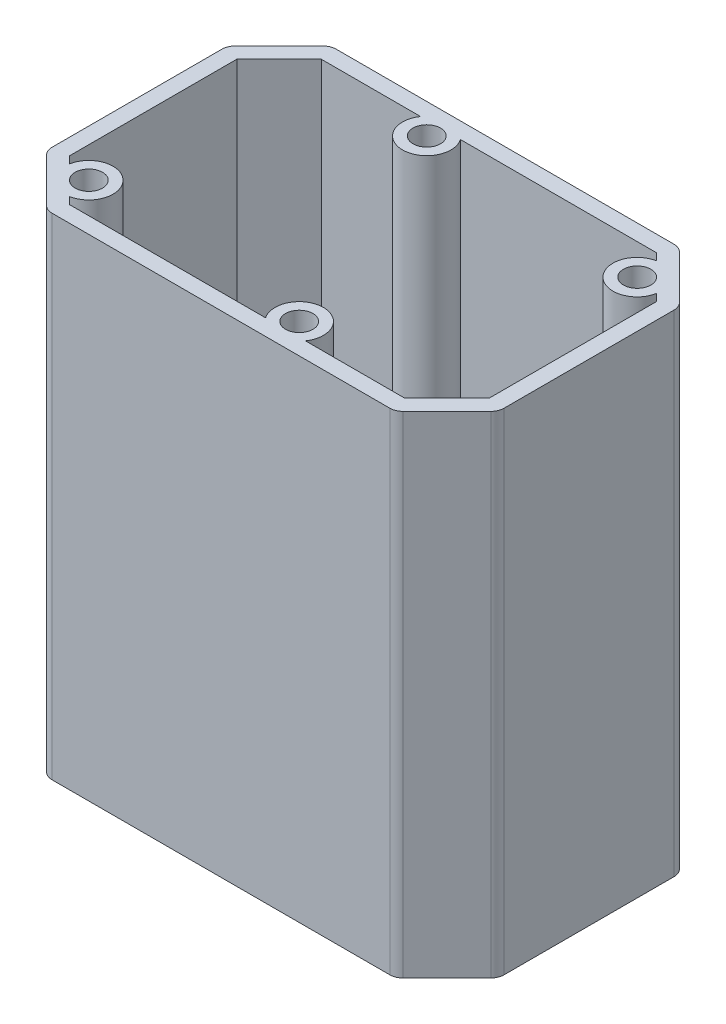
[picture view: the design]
ISO-10303-21;
HEADER;
FILE_DESCRIPTION(('STEP AP214'),'2;1');
FILE_NAME('part.step','',(''),(''),'','','');
FILE_SCHEMA(('AUTOMOTIVE_DESIGN { 1 0 10303 214 1 1 1 1 }'));
ENDSEC;
DATA;
#1=APPLICATION_CONTEXT('core data for automotive mechanical design processes');
#2=APPLICATION_PROTOCOL_DEFINITION('international standard','automotive_design',2000,#1);
#3=PRODUCT_CONTEXT('',#1,'mechanical');
#4=PRODUCT('Part','Part','',(#3));
#5=PRODUCT_RELATED_PRODUCT_CATEGORY('part','',(#4));
#6=PRODUCT_DEFINITION_FORMATION('','',#4);
#7=PRODUCT_DEFINITION_CONTEXT('part definition',#1,'design');
#8=PRODUCT_DEFINITION('design','',#6,#7);
#9=PRODUCT_DEFINITION_SHAPE('','',#8);
#10=(LENGTH_UNIT() NAMED_UNIT(*) SI_UNIT(.MILLI.,.METRE.));
#11=(NAMED_UNIT(*) PLANE_ANGLE_UNIT() SI_UNIT($,.RADIAN.));
#12=(NAMED_UNIT(*) SI_UNIT($,.STERADIAN.) SOLID_ANGLE_UNIT());
#13=UNCERTAINTY_MEASURE_WITH_UNIT(LENGTH_MEASURE(1.E-05),#10,'distance_accuracy_value','');
#14=(GEOMETRIC_REPRESENTATION_CONTEXT(3) GLOBAL_UNCERTAINTY_ASSIGNED_CONTEXT((#13)) GLOBAL_UNIT_ASSIGNED_CONTEXT((#10,
#11,#12)) REPRESENTATION_CONTEXT('',''));
#15=CARTESIAN_POINT('',(0.,0.,0.));
#16=DIRECTION('',(0.,0.,1.));
#17=DIRECTION('',(1.,0.,0.));
#18=AXIS2_PLACEMENT_3D('',#15,#16,#17);
#19=CARTESIAN_POINT('',(24.5000000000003,76.,-24.5000000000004));
#20=DIRECTION('',(-0.707106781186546,0.,0.707106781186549));
#21=DIRECTION('',(0.707106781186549,0.,0.707106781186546));
#22=AXIS2_PLACEMENT_3D('',#19,#20,#21);
#23=PLANE('',#22);
#24=DIRECTION('',(-0.707106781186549,0.,-0.707106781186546));
#25=VECTOR('',#24,1.);
#26=CARTESIAN_POINT('',(24.5000000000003,0.,-24.5000000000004));
#27=LINE('',#26,#25);
#28=CARTESIAN_POINT('',(34.4142135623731,0.,-14.5857864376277));
#29=VERTEX_POINT('',#28);
#30=CARTESIAN_POINT('',(27.5857864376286,0.,-21.4142135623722));
#31=VERTEX_POINT('',#30);
#32=EDGE_CURVE('E337',#29,#31,#27,.T.);
#33=ORIENTED_EDGE('',*,*,#32,.T.);
#34=DIRECTION('',(0.,-1.,0.));
#35=VECTOR('',#34,1.);
#36=CARTESIAN_POINT('',(27.5857864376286,76.,-21.4142135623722));
#37=LINE('',#36,#35);
#38=CARTESIAN_POINT('',(27.5857864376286,76.,-21.4142135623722));
#39=VERTEX_POINT('',#38);
#40=EDGE_CURVE('E11',#39,#31,#37,.T.);
#41=ORIENTED_EDGE('',*,*,#40,.F.);
#42=DIRECTION('',(-0.707106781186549,0.,-0.707106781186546));
#43=VECTOR('',#42,1.);
#44=CARTESIAN_POINT('',(24.5000000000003,76.,-24.5000000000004));
#45=LINE('',#44,#43);
#46=CARTESIAN_POINT('',(34.4142135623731,76.,-14.5857864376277));
#47=VERTEX_POINT('',#46);
#48=EDGE_CURVE('E914',#47,#39,#45,.T.);
#49=ORIENTED_EDGE('',*,*,#48,.F.);
#50=DIRECTION('',(0.,-1.,0.));
#51=VECTOR('',#50,1.);
#52=CARTESIAN_POINT('',(34.4142135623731,76.,-14.5857864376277));
#53=LINE('',#52,#51);
#54=EDGE_CURVE('E368',#47,#29,#53,.T.);
#55=ORIENTED_EDGE('',*,*,#54,.T.);
#56=EDGE_LOOP('',(#33,#41,#49,#55));
#57=FACE_BOUND('',#56,.T.);
#58=ADVANCED_FACE('F41',(#57),#23,.F.);
#59=CARTESIAN_POINT('',(26.1715728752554,76.,-19.9999999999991));
#60=DIRECTION('',(0.,-1.,0.));
#61=DIRECTION('',(0.,0.,-1.));
#62=AXIS2_PLACEMENT_3D('',#59,#60,#61);
#63=CYLINDRICAL_SURFACE('',#62,2.00000000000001);
#64=CARTESIAN_POINT('',(26.1715728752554,0.,-19.9999999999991));
#65=DIRECTION('',(0.,1.,0.));
#66=DIRECTION('',(0.,0.,1.));
#67=AXIS2_PLACEMENT_3D('',#64,#65,#66);
#68=CIRCLE('',#67,2.00000000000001);
#69=CARTESIAN_POINT('',(26.1715728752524,0.,-21.9999999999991));
#70=VERTEX_POINT('',#69);
#71=EDGE_CURVE('E340',#31,#70,#68,.T.);
#72=ORIENTED_EDGE('',*,*,#71,.T.);
#73=DIRECTION('',(0.,-1.,0.));
#74=VECTOR('',#73,1.);
#75=CARTESIAN_POINT('',(26.1715728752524,76.,-21.9999999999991));
#76=LINE('',#75,#74);
#77=CARTESIAN_POINT('',(26.1715728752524,76.,-21.9999999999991));
#78=VERTEX_POINT('',#77);
#79=EDGE_CURVE('E51',#78,#70,#76,.T.);
#80=ORIENTED_EDGE('',*,*,#79,.F.);
#81=CARTESIAN_POINT('',(26.1715728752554,76.,-19.9999999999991));
#82=DIRECTION('',(0.,1.,0.));
#83=DIRECTION('',(0.,0.,1.));
#84=AXIS2_PLACEMENT_3D('',#81,#82,#83);
#85=CIRCLE('',#84,2.00000000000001);
#86=EDGE_CURVE('E915',#39,#78,#85,.T.);
#87=ORIENTED_EDGE('',*,*,#86,.F.);
#88=ORIENTED_EDGE('',*,*,#40,.T.);
#89=EDGE_LOOP('',(#72,#80,#87,#88));
#90=FACE_BOUND('',#89,.T.);
#91=ADVANCED_FACE('F531',(#90),#63,.T.);
#92=CARTESIAN_POINT('',(3.42681749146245E-13,76.,-21.9999999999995));
#93=DIRECTION('',(0.,0.,1.));
#94=DIRECTION('',(1.,0.,0.));
#95=AXIS2_PLACEMENT_3D('',#92,#93,#94);
#96=PLANE('',#95);
#97=DIRECTION('',(-1.,0.,0.));
#98=VECTOR('',#97,1.);
#99=CARTESIAN_POINT('',(3.42681749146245E-13,0.,-21.9999999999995));
#100=LINE('',#99,#98);
#101=CARTESIAN_POINT('',(-26.1715728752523,0.,-21.9999999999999));
#102=VERTEX_POINT('',#101);
#103=EDGE_CURVE('E342',#70,#102,#100,.T.);
#104=ORIENTED_EDGE('',*,*,#103,.T.);
#105=DIRECTION('',(0.,-1.,0.));
#106=VECTOR('',#105,1.);
#107=CARTESIAN_POINT('',(-26.1715728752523,76.,-21.9999999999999));
#108=LINE('',#107,#106);
#109=CARTESIAN_POINT('',(-26.1715728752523,76.,-21.9999999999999));
#110=VERTEX_POINT('',#109);
#111=EDGE_CURVE('E399',#110,#102,#108,.T.);
#112=ORIENTED_EDGE('',*,*,#111,.F.);
#113=DIRECTION('',(-1.,0.,0.));
#114=VECTOR('',#113,1.);
#115=CARTESIAN_POINT('',(3.42681749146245E-13,76.,-21.9999999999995));
#116=LINE('',#115,#114);
#117=EDGE_CURVE('E917',#78,#110,#116,.T.);
#118=ORIENTED_EDGE('',*,*,#117,.F.);
#119=ORIENTED_EDGE('',*,*,#79,.T.);
#120=EDGE_LOOP('',(#104,#112,#118,#119));
#121=FACE_BOUND('',#120,.T.);
#122=ADVANCED_FACE('F537',(#121),#96,.F.);
#123=CARTESIAN_POINT('',(-26.1715728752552,76.,-19.9999999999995));
#124=DIRECTION('',(0.,-1.,0.));
#125=DIRECTION('',(0.,0.,-1.));
#126=AXIS2_PLACEMENT_3D('',#123,#124,#125);
#127=CYLINDRICAL_SURFACE('',#126,2.00000000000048);
#128=CARTESIAN_POINT('',(-26.1715728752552,0.,-19.9999999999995));
#129=DIRECTION('',(0.,1.,0.));
#130=DIRECTION('',(0.,0.,1.));
#131=AXIS2_PLACEMENT_3D('',#128,#129,#130);
#132=CIRCLE('',#131,2.00000000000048);
#133=CARTESIAN_POINT('',(-27.5857864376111,0.,-21.4142135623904));
#134=VERTEX_POINT('',#133);
#135=EDGE_CURVE('E344',#102,#134,#132,.T.);
#136=ORIENTED_EDGE('',*,*,#135,.T.);
#137=DIRECTION('',(0.,-1.,0.));
#138=VECTOR('',#137,1.);
#139=CARTESIAN_POINT('',(-27.5857864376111,76.,-21.4142135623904));
#140=LINE('',#139,#138);
#141=CARTESIAN_POINT('',(-27.5857864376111,76.,-21.4142135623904));
#142=VERTEX_POINT('',#141);
#143=EDGE_CURVE('E396',#142,#134,#140,.T.);
#144=ORIENTED_EDGE('',*,*,#143,.F.);
#145=CARTESIAN_POINT('',(-26.1715728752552,76.,-19.9999999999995));
#146=DIRECTION('',(0.,1.,0.));
#147=DIRECTION('',(0.,0.,1.));
#148=AXIS2_PLACEMENT_3D('',#145,#146,#147);
#149=CIRCLE('',#148,2.00000000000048);
#150=EDGE_CURVE('E879',#110,#142,#149,.T.);
#151=ORIENTED_EDGE('',*,*,#150,.F.);
#152=ORIENTED_EDGE('',*,*,#111,.T.);
#153=EDGE_LOOP('',(#136,#144,#151,#152));
#154=FACE_BOUND('',#153,.T.);
#155=ADVANCED_FACE('F828',(#154),#127,.T.);
#156=CARTESIAN_POINT('',(-24.5000000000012,76.,-24.5000000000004));
#157=DIRECTION('',(0.707106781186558,0.,0.707106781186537));
#158=DIRECTION('',(0.707106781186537,0.,-0.707106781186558));
#159=AXIS2_PLACEMENT_3D('',#156,#157,#158);
#160=PLANE('',#159);
#161=DIRECTION('',(-0.707106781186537,0.,0.707106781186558));
#162=VECTOR('',#161,1.);
#163=CARTESIAN_POINT('',(-24.5000000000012,0.,-24.5000000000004));
#164=LINE('',#163,#162);
#165=CARTESIAN_POINT('',(-34.4142135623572,0.,-14.5857864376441));
#166=VERTEX_POINT('',#165);
#167=EDGE_CURVE('E346',#134,#166,#164,.T.);
#168=ORIENTED_EDGE('',*,*,#167,.T.);
#169=DIRECTION('',(0.,-1.,0.));
#170=VECTOR('',#169,1.);
#171=CARTESIAN_POINT('',(-34.4142135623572,76.,-14.5857864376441));
#172=LINE('',#171,#170);
#173=CARTESIAN_POINT('',(-34.4142135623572,76.,-14.5857864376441));
#174=VERTEX_POINT('',#173);
#175=EDGE_CURVE('E393',#174,#166,#172,.T.);
#176=ORIENTED_EDGE('',*,*,#175,.F.);
#177=DIRECTION('',(-0.707106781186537,0.,0.707106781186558));
#178=VECTOR('',#177,1.);
#179=CARTESIAN_POINT('',(-24.5000000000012,76.,-24.5000000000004));
#180=LINE('',#179,#178);
#181=EDGE_CURVE('E891',#142,#174,#180,.T.);
#182=ORIENTED_EDGE('',*,*,#181,.F.);
#183=ORIENTED_EDGE('',*,*,#143,.T.);
#184=EDGE_LOOP('',(#168,#176,#182,#183));
#185=FACE_BOUND('',#184,.T.);
#186=ADVANCED_FACE('F819',(#185),#160,.F.);
#187=CARTESIAN_POINT('',(-32.9999999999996,76.,-13.1715728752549));
#188=DIRECTION('',(0.,-1.,0.));
#189=DIRECTION('',(0.,0.,-1.));
#190=AXIS2_PLACEMENT_3D('',#187,#188,#189);
#191=CYLINDRICAL_SURFACE('',#190,2.00000000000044);
#192=CARTESIAN_POINT('',(-32.9999999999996,0.,-13.1715728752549));
#193=DIRECTION('',(0.,1.,0.));
#194=DIRECTION('',(0.,0.,1.));
#195=AXIS2_PLACEMENT_3D('',#192,#193,#194);
#196=CIRCLE('',#195,2.00000000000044);
#197=CARTESIAN_POINT('',(-35.,0.,-13.1715728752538));
#198=VERTEX_POINT('',#197);
#199=EDGE_CURVE('E348',#166,#198,#196,.T.);
#200=ORIENTED_EDGE('',*,*,#199,.T.);
#201=DIRECTION('',(0.,-1.,0.));
#202=VECTOR('',#201,1.);
#203=CARTESIAN_POINT('',(-35.,76.,-13.1715728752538));
#204=LINE('',#203,#202);
#205=CARTESIAN_POINT('',(-35.,76.,-13.1715728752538));
#206=VERTEX_POINT('',#205);
#207=EDGE_CURVE('E390',#206,#198,#204,.T.);
#208=ORIENTED_EDGE('',*,*,#207,.F.);
#209=CARTESIAN_POINT('',(-32.9999999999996,76.,-13.1715728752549));
#210=DIRECTION('',(0.,1.,0.));
#211=DIRECTION('',(0.,0.,1.));
#212=AXIS2_PLACEMENT_3D('',#209,#210,#211);
#213=CIRCLE('',#212,2.00000000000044);
#214=EDGE_CURVE('E888',#174,#206,#213,.T.);
#215=ORIENTED_EDGE('',*,*,#214,.F.);
#216=ORIENTED_EDGE('',*,*,#175,.T.);
#217=EDGE_LOOP('',(#200,#208,#215,#216));
#218=FACE_BOUND('',#217,.T.);
#219=ADVANCED_FACE('F810',(#218),#191,.T.);
#220=CARTESIAN_POINT('',(-35.,76.,0.));
#221=DIRECTION('',(1.,0.,0.));
#222=DIRECTION('',(0.,0.,-1.));
#223=AXIS2_PLACEMENT_3D('',#220,#221,#222);
#224=PLANE('',#223);
#225=DIRECTION('',(0.,0.,1.));
#226=VECTOR('',#225,1.);
#227=CARTESIAN_POINT('',(-35.,0.,0.));
#228=LINE('',#227,#226);
#229=CARTESIAN_POINT('',(-35.,0.,13.1715728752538));
#230=VERTEX_POINT('',#229);
#231=EDGE_CURVE('E350',#198,#230,#228,.T.);
#232=ORIENTED_EDGE('',*,*,#231,.T.);
#233=DIRECTION('',(0.,-1.,0.));
#234=VECTOR('',#233,1.);
#235=CARTESIAN_POINT('',(-35.,76.,13.1715728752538));
#236=LINE('',#235,#234);
#237=CARTESIAN_POINT('',(-35.,76.,13.1715728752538));
#238=VERTEX_POINT('',#237);
#239=EDGE_CURVE('E387',#238,#230,#236,.T.);
#240=ORIENTED_EDGE('',*,*,#239,.F.);
#241=DIRECTION('',(0.,0.,1.));
#242=VECTOR('',#241,1.);
#243=CARTESIAN_POINT('',(-35.,76.,0.));
#244=LINE('',#243,#242);
#245=EDGE_CURVE('E890',#206,#238,#244,.T.);
#246=ORIENTED_EDGE('',*,*,#245,.F.);
#247=ORIENTED_EDGE('',*,*,#207,.T.);
#248=EDGE_LOOP('',(#232,#240,#246,#247));
#249=FACE_BOUND('',#248,.T.);
#250=ADVANCED_FACE('F801',(#249),#224,.F.);
#251=CARTESIAN_POINT('',(-33.,76.,13.1715728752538));
#252=DIRECTION('',(0.,-1.,0.));
#253=DIRECTION('',(0.,0.,-1.));
#254=AXIS2_PLACEMENT_3D('',#251,#252,#253);
#255=CYLINDRICAL_SURFACE('',#254,2.);
#256=CARTESIAN_POINT('',(-33.,0.,13.1715728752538));
#257=DIRECTION('',(0.,1.,0.));
#258=DIRECTION('',(0.,0.,1.));
#259=AXIS2_PLACEMENT_3D('',#256,#257,#258);
#260=CIRCLE('',#259,2.);
#261=CARTESIAN_POINT('',(-34.4142135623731,0.,14.5857864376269));
#262=VERTEX_POINT('',#261);
#263=EDGE_CURVE('E352',#230,#262,#260,.T.);
#264=ORIENTED_EDGE('',*,*,#263,.T.);
#265=DIRECTION('',(0.,-1.,0.));
#266=VECTOR('',#265,1.);
#267=CARTESIAN_POINT('',(-34.4142135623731,76.,14.5857864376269));
#268=LINE('',#267,#266);
#269=CARTESIAN_POINT('',(-34.4142135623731,76.,14.5857864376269));
#270=VERTEX_POINT('',#269);
#271=EDGE_CURVE('E384',#270,#262,#268,.T.);
#272=ORIENTED_EDGE('',*,*,#271,.F.);
#273=CARTESIAN_POINT('',(-33.,76.,13.1715728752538));
#274=DIRECTION('',(0.,1.,0.));
#275=DIRECTION('',(0.,0.,1.));
#276=AXIS2_PLACEMENT_3D('',#273,#274,#275);
#277=CIRCLE('',#276,2.);
#278=EDGE_CURVE('E893',#238,#270,#277,.T.);
#279=ORIENTED_EDGE('',*,*,#278,.F.);
#280=ORIENTED_EDGE('',*,*,#239,.T.);
#281=EDGE_LOOP('',(#264,#272,#279,#280));
#282=FACE_BOUND('',#281,.T.);
#283=ADVANCED_FACE('F792',(#282),#255,.T.);
#284=CARTESIAN_POINT('',(-24.4999999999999,76.,24.5));
#285=DIRECTION('',(0.707106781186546,0.,-0.707106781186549));
#286=DIRECTION('',(-0.707106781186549,0.,-0.707106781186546));
#287=AXIS2_PLACEMENT_3D('',#284,#285,#286);
#288=PLANE('',#287);
#289=DIRECTION('',(0.707106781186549,0.,0.707106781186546));
#290=VECTOR('',#289,1.);
#291=CARTESIAN_POINT('',(-24.4999999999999,0.,24.5));
#292=LINE('',#291,#290);
#293=CARTESIAN_POINT('',(-27.5857864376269,0.,21.4142135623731));
#294=VERTEX_POINT('',#293);
#295=EDGE_CURVE('E354',#262,#294,#292,.T.);
#296=ORIENTED_EDGE('',*,*,#295,.T.);
#297=DIRECTION('',(0.,-1.,0.));
#298=VECTOR('',#297,1.);
#299=CARTESIAN_POINT('',(-27.5857864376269,76.,21.4142135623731));
#300=LINE('',#299,#298);
#301=CARTESIAN_POINT('',(-27.5857864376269,76.,21.4142135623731));
#302=VERTEX_POINT('',#301);
#303=EDGE_CURVE('E381',#302,#294,#300,.T.);
#304=ORIENTED_EDGE('',*,*,#303,.F.);
#305=DIRECTION('',(0.707106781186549,0.,0.707106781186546));
#306=VECTOR('',#305,1.);
#307=CARTESIAN_POINT('',(-24.4999999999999,76.,24.5));
#308=LINE('',#307,#306);
#309=EDGE_CURVE('E899',#270,#302,#308,.T.);
#310=ORIENTED_EDGE('',*,*,#309,.F.);
#311=ORIENTED_EDGE('',*,*,#271,.T.);
#312=EDGE_LOOP('',(#296,#304,#310,#311));
#313=FACE_BOUND('',#312,.T.);
#314=ADVANCED_FACE('F783',(#313),#288,.F.);
#315=CARTESIAN_POINT('',(-26.1715728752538,76.,20.));
#316=DIRECTION('',(0.,-1.,0.));
#317=DIRECTION('',(0.,0.,-1.));
#318=AXIS2_PLACEMENT_3D('',#315,#316,#317);
#319=CYLINDRICAL_SURFACE('',#318,1.99999999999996);
#320=CARTESIAN_POINT('',(-26.1715728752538,0.,20.));
#321=DIRECTION('',(0.,1.,0.));
#322=DIRECTION('',(0.,0.,1.));
#323=AXIS2_PLACEMENT_3D('',#320,#321,#322);
#324=CIRCLE('',#323,1.99999999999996);
#325=CARTESIAN_POINT('',(-26.1715728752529,0.,22.));
#326=VERTEX_POINT('',#325);
#327=EDGE_CURVE('E356',#294,#326,#324,.T.);
#328=ORIENTED_EDGE('',*,*,#327,.T.);
#329=DIRECTION('',(0.,-1.,0.));
#330=VECTOR('',#329,1.);
#331=CARTESIAN_POINT('',(-26.1715728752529,76.,22.));
#332=LINE('',#331,#330);
#333=CARTESIAN_POINT('',(-26.1715728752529,76.,22.));
#334=VERTEX_POINT('',#333);
#335=EDGE_CURVE('E378',#334,#326,#332,.T.);
#336=ORIENTED_EDGE('',*,*,#335,.F.);
#337=CARTESIAN_POINT('',(-26.1715728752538,76.,20.));
#338=DIRECTION('',(0.,1.,0.));
#339=DIRECTION('',(0.,0.,1.));
#340=AXIS2_PLACEMENT_3D('',#337,#338,#339);
#341=CIRCLE('',#340,1.99999999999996);
#342=EDGE_CURVE('E901',#302,#334,#341,.T.);
#343=ORIENTED_EDGE('',*,*,#342,.F.);
#344=ORIENTED_EDGE('',*,*,#303,.T.);
#345=EDGE_LOOP('',(#328,#336,#343,#344));
#346=FACE_BOUND('',#345,.T.);
#347=ADVANCED_FACE('F774',(#346),#319,.T.);
#348=CARTESIAN_POINT('',(-3.45598189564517E-13,76.,22.0000000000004));
#349=DIRECTION('',(0.,0.,-1.));
#350=DIRECTION('',(-1.,0.,0.));
#351=AXIS2_PLACEMENT_3D('',#348,#349,#350);
#352=PLANE('',#351);
#353=DIRECTION('',(1.,0.,0.));
#354=VECTOR('',#353,1.);
#355=CARTESIAN_POINT('',(-3.45598189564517E-13,0.,22.0000000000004));
#356=LINE('',#355,#354);
#357=CARTESIAN_POINT('',(26.1715728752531,0.,22.0000000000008));
#358=VERTEX_POINT('',#357);
#359=EDGE_CURVE('E358',#326,#358,#356,.T.);
#360=ORIENTED_EDGE('',*,*,#359,.T.);
#361=DIRECTION('',(0.,-1.,0.));
#362=VECTOR('',#361,1.);
#363=CARTESIAN_POINT('',(26.1715728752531,76.,22.0000000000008));
#364=LINE('',#363,#362);
#365=CARTESIAN_POINT('',(26.1715728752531,76.,22.0000000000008));
#366=VERTEX_POINT('',#365);
#367=EDGE_CURVE('E375',#366,#358,#364,.T.);
#368=ORIENTED_EDGE('',*,*,#367,.F.);
#369=DIRECTION('',(1.,0.,0.));
#370=VECTOR('',#369,1.);
#371=CARTESIAN_POINT('',(-3.45598189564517E-13,76.,22.0000000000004));
#372=LINE('',#371,#370);
#373=EDGE_CURVE('E903',#334,#366,#372,.T.);
#374=ORIENTED_EDGE('',*,*,#373,.F.);
#375=ORIENTED_EDGE('',*,*,#335,.T.);
#376=EDGE_LOOP('',(#360,#368,#374,#375));
#377=FACE_BOUND('',#376,.T.);
#378=ADVANCED_FACE('F765',(#377),#352,.F.);
#379=CARTESIAN_POINT('',(26.1715728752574,76.,20.0000000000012));
#380=DIRECTION('',(0.,-1.,0.));
#381=DIRECTION('',(0.,0.,-1.));
#382=AXIS2_PLACEMENT_3D('',#379,#380,#381);
#383=CYLINDRICAL_SURFACE('',#382,1.99999999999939);
#384=CARTESIAN_POINT('',(26.1715728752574,0.,20.0000000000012));
#385=DIRECTION('',(0.,1.,0.));
#386=DIRECTION('',(0.,0.,1.));
#387=AXIS2_PLACEMENT_3D('',#384,#385,#386);
#388=CIRCLE('',#387,1.99999999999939);
#389=CARTESIAN_POINT('',(27.5857864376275,0.,21.4142135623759));
#390=VERTEX_POINT('',#389);
#391=EDGE_CURVE('E360',#358,#390,#388,.T.);
#392=ORIENTED_EDGE('',*,*,#391,.T.);
#393=DIRECTION('',(0.,-1.,0.));
#394=VECTOR('',#393,1.);
#395=CARTESIAN_POINT('',(27.5857864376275,76.,21.4142135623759));
#396=LINE('',#395,#394);
#397=CARTESIAN_POINT('',(27.5857864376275,76.,21.4142135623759));
#398=VERTEX_POINT('',#397);
#399=EDGE_CURVE('E372',#398,#390,#396,.T.);
#400=ORIENTED_EDGE('',*,*,#399,.F.);
#401=CARTESIAN_POINT('',(26.1715728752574,76.,20.0000000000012));
#402=DIRECTION('',(0.,1.,0.));
#403=DIRECTION('',(0.,0.,1.));
#404=AXIS2_PLACEMENT_3D('',#401,#402,#403);
#405=CIRCLE('',#404,1.99999999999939);
#406=EDGE_CURVE('E905',#366,#398,#405,.T.);
#407=ORIENTED_EDGE('',*,*,#406,.F.);
#408=ORIENTED_EDGE('',*,*,#367,.T.);
#409=EDGE_LOOP('',(#392,#400,#407,#408));
#410=FACE_BOUND('',#409,.T.);
#411=ADVANCED_FACE('F756',(#410),#383,.T.);
#412=CARTESIAN_POINT('',(24.5000000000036,76.,24.5000000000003));
#413=DIRECTION('',(-0.707106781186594,0.,-0.707106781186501));
#414=DIRECTION('',(-0.707106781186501,0.,0.707106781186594));
#415=AXIS2_PLACEMENT_3D('',#412,#413,#414);
#416=PLANE('',#415);
#417=DIRECTION('',(0.707106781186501,0.,-0.707106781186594));
#418=VECTOR('',#417,1.);
#419=CARTESIAN_POINT('',(24.5000000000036,0.,24.5000000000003));
#420=LINE('',#419,#418);
#421=CARTESIAN_POINT('',(34.4142135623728,0.,14.5857864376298));
#422=VERTEX_POINT('',#421);
#423=EDGE_CURVE('E362',#390,#422,#420,.T.);
#424=ORIENTED_EDGE('',*,*,#423,.T.);
#425=DIRECTION('',(0.,-1.,0.));
#426=VECTOR('',#425,1.);
#427=CARTESIAN_POINT('',(34.4142135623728,76.,14.5857864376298));
#428=LINE('',#427,#426);
#429=CARTESIAN_POINT('',(34.4142135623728,76.,14.5857864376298));
#430=VERTEX_POINT('',#429);
#431=EDGE_CURVE('E276',#430,#422,#428,.T.);
#432=ORIENTED_EDGE('',*,*,#431,.F.);
#433=DIRECTION('',(0.707106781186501,0.,-0.707106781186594));
#434=VECTOR('',#433,1.);
#435=CARTESIAN_POINT('',(24.5000000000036,76.,24.5000000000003));
#436=LINE('',#435,#434);
#437=EDGE_CURVE('E267',#398,#430,#436,.T.);
#438=ORIENTED_EDGE('',*,*,#437,.F.);
#439=ORIENTED_EDGE('',*,*,#399,.T.);
#440=EDGE_LOOP('',(#424,#432,#438,#439));
#441=FACE_BOUND('',#440,.T.);
#442=ADVANCED_FACE('F748',(#441),#416,.F.);
#443=CARTESIAN_POINT('',(32.9999999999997,76.,13.1715728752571));
#444=DIRECTION('',(0.,-1.,0.));
#445=DIRECTION('',(0.,0.,-1.));
#446=AXIS2_PLACEMENT_3D('',#443,#444,#445);
#447=CYLINDRICAL_SURFACE('',#446,2.00000000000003);
#448=CARTESIAN_POINT('',(32.9999999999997,0.,13.1715728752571));
#449=DIRECTION('',(0.,1.,0.));
#450=DIRECTION('',(0.,0.,1.));
#451=AXIS2_PLACEMENT_3D('',#448,#449,#450);
#452=CIRCLE('',#451,2.00000000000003);
#453=CARTESIAN_POINT('',(35.,0.,13.1715728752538));
#454=VERTEX_POINT('',#453);
#455=EDGE_CURVE('E275',#422,#454,#452,.T.);
#456=ORIENTED_EDGE('',*,*,#455,.T.);
#457=DIRECTION('',(0.,-1.,0.));
#458=VECTOR('',#457,1.);
#459=CARTESIAN_POINT('',(35.,76.,13.1715728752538));
#460=LINE('',#459,#458);
#461=CARTESIAN_POINT('',(35.,76.,13.1715728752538));
#462=VERTEX_POINT('',#461);
#463=EDGE_CURVE('E272',#462,#454,#460,.T.);
#464=ORIENTED_EDGE('',*,*,#463,.F.);
#465=CARTESIAN_POINT('',(32.9999999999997,76.,13.1715728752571));
#466=DIRECTION('',(0.,1.,0.));
#467=DIRECTION('',(0.,0.,1.));
#468=AXIS2_PLACEMENT_3D('',#465,#466,#467);
#469=CIRCLE('',#468,2.00000000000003);
#470=EDGE_CURVE('E261',#430,#462,#469,.T.);
#471=ORIENTED_EDGE('',*,*,#470,.F.);
#472=ORIENTED_EDGE('',*,*,#431,.T.);
#473=EDGE_LOOP('',(#456,#464,#471,#472));
#474=FACE_BOUND('',#473,.T.);
#475=ADVANCED_FACE('F273',(#474),#447,.T.);
#476=CARTESIAN_POINT('',(35.,76.,0.));
#477=DIRECTION('',(-1.,0.,0.));
#478=DIRECTION('',(0.,0.,1.));
#479=AXIS2_PLACEMENT_3D('',#476,#477,#478);
#480=PLANE('',#479);
#481=DIRECTION('',(0.,0.,-1.));
#482=VECTOR('',#481,1.);
#483=CARTESIAN_POINT('',(35.,0.,0.));
#484=LINE('',#483,#482);
#485=CARTESIAN_POINT('',(35.,0.,-13.1715728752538));
#486=VERTEX_POINT('',#485);
#487=EDGE_CURVE('E161',#454,#486,#484,.T.);
#488=ORIENTED_EDGE('',*,*,#487,.T.);
#489=DIRECTION('',(0.,-1.,0.));
#490=VECTOR('',#489,1.);
#491=CARTESIAN_POINT('',(35.,76.,-13.1715728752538));
#492=LINE('',#491,#490);
#493=CARTESIAN_POINT('',(35.,76.,-13.1715728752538));
#494=VERTEX_POINT('',#493);
#495=EDGE_CURVE('E277',#494,#486,#492,.T.);
#496=ORIENTED_EDGE('',*,*,#495,.F.);
#497=DIRECTION('',(0.,0.,-1.));
#498=VECTOR('',#497,1.);
#499=CARTESIAN_POINT('',(35.,76.,0.));
#500=LINE('',#499,#498);
#501=EDGE_CURVE('E265',#462,#494,#500,.T.);
#502=ORIENTED_EDGE('',*,*,#501,.F.);
#503=ORIENTED_EDGE('',*,*,#463,.T.);
#504=EDGE_LOOP('',(#488,#496,#502,#503));
#505=FACE_BOUND('',#504,.T.);
#506=ADVANCED_FACE('F279',(#505),#480,.F.);
#507=CARTESIAN_POINT('',(-22.7322330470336,76.,22.7322330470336));
#508=DIRECTION('',(0.707106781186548,0.,-0.707106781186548));
#509=DIRECTION('',(-0.707106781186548,0.,-0.707106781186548));
#510=AXIS2_PLACEMENT_3D('',#507,#508,#509);
#511=PLANE('',#510);
#512=DIRECTION('',(0.707106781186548,0.,0.707106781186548));
#513=VECTOR('',#512,1.);
#514=CARTESIAN_POINT('',(-22.7322330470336,0.,22.7322330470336));
#515=LINE('',#514,#513);
#516=CARTESIAN_POINT('',(-27.047413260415,0.,18.4170528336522));
#517=VERTEX_POINT('',#516);
#518=CARTESIAN_POINT('',(-25.9644660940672,0.,19.5));
#519=VERTEX_POINT('',#518);
#520=EDGE_CURVE('E297',#517,#519,#515,.T.);
#521=ORIENTED_EDGE('',*,*,#520,.F.);
#522=DIRECTION('',(0.,-1.,0.));
#523=VECTOR('',#522,1.);
#524=CARTESIAN_POINT('',(-27.047413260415,76.,18.4170528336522));
#525=LINE('',#524,#523);
#526=CARTESIAN_POINT('',(-27.047413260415,76.,18.4170528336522));
#527=VERTEX_POINT('',#526);
#528=EDGE_CURVE('E45',#527,#517,#525,.T.);
#529=ORIENTED_EDGE('',*,*,#528,.F.);
#530=DIRECTION('',(0.707106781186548,0.,0.707106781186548));
#531=VECTOR('',#530,1.);
#532=CARTESIAN_POINT('',(-22.7322330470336,76.,22.7322330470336));
#533=LINE('',#532,#531);
#534=CARTESIAN_POINT('',(-25.9644660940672,76.,19.5));
#535=VERTEX_POINT('',#534);
#536=EDGE_CURVE('E447',#527,#535,#533,.T.);
#537=ORIENTED_EDGE('',*,*,#536,.T.);
#538=DIRECTION('',(0.,-1.,0.));
#539=VECTOR('',#538,1.);
#540=CARTESIAN_POINT('',(-25.9644660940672,76.,19.5));
#541=LINE('',#540,#539);
#542=EDGE_CURVE('E281',#535,#519,#541,.T.);
#543=ORIENTED_EDGE('',*,*,#542,.T.);
#544=EDGE_LOOP('',(#521,#529,#537,#543));
#545=FACE_BOUND('',#544,.T.);
#546=ADVANCED_FACE('F446',(#545),#511,.T.);
#547=CARTESIAN_POINT('',(-27.7296311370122,76.,14.7296311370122));
#548=DIRECTION('',(0.,-1.,0.));
#549=DIRECTION('',(0.,0.,-1.));
#550=AXIS2_PLACEMENT_3D('',#547,#548,#549);
#551=CYLINDRICAL_SURFACE('',#550,3.75);
#552=CARTESIAN_POINT('',(-27.7296311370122,0.,14.7296311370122));
#553=DIRECTION('',(0.,1.,0.));
#554=DIRECTION('',(0.,0.,1.));
#555=AXIS2_PLACEMENT_3D('',#552,#553,#554);
#556=CIRCLE('',#555,3.75);
#557=CARTESIAN_POINT('',(-31.4170528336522,0.,14.0474132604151));
#558=VERTEX_POINT('',#557);
#559=EDGE_CURVE('E300',#517,#558,#556,.T.);
#560=ORIENTED_EDGE('',*,*,#559,.T.);
#561=DIRECTION('',(0.,-1.,0.));
#562=VECTOR('',#561,1.);
#563=CARTESIAN_POINT('',(-31.4170528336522,76.,14.0474132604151));
#564=LINE('',#563,#562);
#565=CARTESIAN_POINT('',(-31.4170528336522,76.,14.0474132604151));
#566=VERTEX_POINT('',#565);
#567=EDGE_CURVE('E430',#566,#558,#564,.T.);
#568=ORIENTED_EDGE('',*,*,#567,.F.);
#569=CARTESIAN_POINT('',(-27.7296311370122,76.,14.7296311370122));
#570=DIRECTION('',(0.,1.,0.));
#571=DIRECTION('',(0.,0.,1.));
#572=AXIS2_PLACEMENT_3D('',#569,#570,#571);
#573=CIRCLE('',#572,3.75);
#574=EDGE_CURVE('E439',#527,#566,#573,.T.);
#575=ORIENTED_EDGE('',*,*,#574,.F.);
#576=ORIENTED_EDGE('',*,*,#528,.T.);
#577=EDGE_LOOP('',(#560,#568,#575,#576));
#578=FACE_BOUND('',#577,.T.);
#579=ADVANCED_FACE('F437',(#578),#551,.T.);
#580=CARTESIAN_POINT('',(-32.5,0.,12.9644660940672));
#581=VERTEX_POINT('',#580);
#582=EDGE_CURVE('E301',#581,#558,#515,.T.);
#583=ORIENTED_EDGE('',*,*,#582,.F.);
#584=DIRECTION('',(0.,-1.,0.));
#585=VECTOR('',#584,1.);
#586=CARTESIAN_POINT('',(-32.5,76.,12.9644660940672));
#587=LINE('',#586,#585);
#588=CARTESIAN_POINT('',(-32.5,76.,12.9644660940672));
#589=VERTEX_POINT('',#588);
#590=EDGE_CURVE('E429',#589,#581,#587,.T.);
#591=ORIENTED_EDGE('',*,*,#590,.F.);
#592=EDGE_CURVE('E937',#589,#566,#533,.T.);
#593=ORIENTED_EDGE('',*,*,#592,.T.);
#594=ORIENTED_EDGE('',*,*,#567,.T.);
#595=EDGE_LOOP('',(#583,#591,#593,#594));
#596=FACE_BOUND('',#595,.T.);
#597=ADVANCED_FACE('F520',(#596),#511,.T.);
#598=CARTESIAN_POINT('',(-32.5,76.,0.));
#599=DIRECTION('',(1.,0.,0.));
#600=DIRECTION('',(0.,0.,-1.));
#601=AXIS2_PLACEMENT_3D('',#598,#599,#600);
#602=PLANE('',#601);
#603=DIRECTION('',(0.,0.,1.));
#604=VECTOR('',#603,1.);
#605=CARTESIAN_POINT('',(-32.5,0.,0.));
#606=LINE('',#605,#604);
#607=CARTESIAN_POINT('',(-32.5,0.,-12.9644660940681));
#608=VERTEX_POINT('',#607);
#609=EDGE_CURVE('E304',#608,#581,#606,.T.);
#610=ORIENTED_EDGE('',*,*,#609,.F.);
#611=DIRECTION('',(0.,-1.,0.));
#612=VECTOR('',#611,1.);
#613=CARTESIAN_POINT('',(-32.5,76.,-12.9644660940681));
#614=LINE('',#613,#612);
#615=CARTESIAN_POINT('',(-32.5,76.,-12.9644660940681));
#616=VERTEX_POINT('',#615);
#617=EDGE_CURVE('E427',#616,#608,#614,.T.);
#618=ORIENTED_EDGE('',*,*,#617,.F.);
#619=DIRECTION('',(0.,0.,1.));
#620=VECTOR('',#619,1.);
#621=CARTESIAN_POINT('',(-32.5,76.,0.));
#622=LINE('',#621,#620);
#623=EDGE_CURVE('E518',#616,#589,#622,.T.);
#624=ORIENTED_EDGE('',*,*,#623,.T.);
#625=ORIENTED_EDGE('',*,*,#590,.T.);
#626=EDGE_LOOP('',(#610,#618,#624,#625));
#627=FACE_BOUND('',#626,.T.);
#628=ADVANCED_FACE('F515',(#627),#602,.T.);
#629=CARTESIAN_POINT('',(-22.7322330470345,76.,-22.7322330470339));
#630=DIRECTION('',(0.707106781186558,0.,0.707106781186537));
#631=DIRECTION('',(0.707106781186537,0.,-0.707106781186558));
#632=AXIS2_PLACEMENT_3D('',#629,#630,#631);
#633=PLANE('',#632);
#634=DIRECTION('',(-0.707106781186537,0.,0.707106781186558));
#635=VECTOR('',#634,1.);
#636=CARTESIAN_POINT('',(-22.7322330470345,0.,-22.7322330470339));
#637=LINE('',#636,#635);
#638=CARTESIAN_POINT('',(-25.9644660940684,0.,-19.4999999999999));
#639=VERTEX_POINT('',#638);
#640=EDGE_CURVE('E307',#639,#608,#637,.T.);
#641=ORIENTED_EDGE('',*,*,#640,.F.);
#642=DIRECTION('',(0.,-1.,0.));
#643=VECTOR('',#642,1.);
#644=CARTESIAN_POINT('',(-25.9644660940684,76.,-19.4999999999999));
#645=LINE('',#644,#643);
#646=CARTESIAN_POINT('',(-25.9644660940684,76.,-19.4999999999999));
#647=VERTEX_POINT('',#646);
#648=EDGE_CURVE('E425',#647,#639,#645,.T.);
#649=ORIENTED_EDGE('',*,*,#648,.F.);
#650=DIRECTION('',(-0.707106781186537,0.,0.707106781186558));
#651=VECTOR('',#650,1.);
#652=CARTESIAN_POINT('',(-22.7322330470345,76.,-22.7322330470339));
#653=LINE('',#652,#651);
#654=EDGE_CURVE('E934',#647,#616,#653,.T.);
#655=ORIENTED_EDGE('',*,*,#654,.T.);
#656=ORIENTED_EDGE('',*,*,#617,.T.);
#657=EDGE_LOOP('',(#641,#649,#655,#656));
#658=FACE_BOUND('',#657,.T.);
#659=ADVANCED_FACE('F512',(#658),#633,.T.);
#660=CARTESIAN_POINT('',(3.03557796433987E-13,76.,-19.4999999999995));
#661=DIRECTION('',(0.,0.,1.));
#662=DIRECTION('',(1.,0.,0.));
#663=AXIS2_PLACEMENT_3D('',#660,#661,#662);
#664=PLANE('',#663);
#665=DIRECTION('',(-1.,0.,0.));
#666=VECTOR('',#665,1.);
#667=CARTESIAN_POINT('',(3.03557796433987E-13,0.,-19.4999999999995));
#668=LINE('',#667,#666);
#669=CARTESIAN_POINT('',(-10.5898017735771,0.,-19.4999999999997));
#670=VERTEX_POINT('',#669);
#671=EDGE_CURVE('E310',#670,#639,#668,.T.);
#672=ORIENTED_EDGE('',*,*,#671,.F.);
#673=DIRECTION('',(0.,-1.,0.));
#674=VECTOR('',#673,1.);
#675=CARTESIAN_POINT('',(-10.5898017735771,76.,-19.4999999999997));
#676=LINE('',#675,#674);
#677=CARTESIAN_POINT('',(-10.5898017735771,76.,-19.4999999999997));
#678=VERTEX_POINT('',#677);
#679=EDGE_CURVE('E423',#678,#670,#676,.T.);
#680=ORIENTED_EDGE('',*,*,#679,.F.);
#681=DIRECTION('',(-1.,0.,0.));
#682=VECTOR('',#681,1.);
#683=CARTESIAN_POINT('',(3.03557796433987E-13,76.,-19.4999999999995));
#684=LINE('',#683,#682);
#685=EDGE_CURVE('E508',#678,#647,#684,.T.);
#686=ORIENTED_EDGE('',*,*,#685,.T.);
#687=ORIENTED_EDGE('',*,*,#648,.T.);
#688=EDGE_LOOP('',(#672,#680,#686,#687));
#689=FACE_BOUND('',#688,.T.);
#690=ADVANCED_FACE('F503',(#689),#664,.T.);
#691=CARTESIAN_POINT('',(-7.50000000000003,76.,-17.3749999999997));
#692=DIRECTION('',(0.,-1.,0.));
#693=DIRECTION('',(0.,0.,-1.));
#694=AXIS2_PLACEMENT_3D('',#691,#692,#693);
#695=CYLINDRICAL_SURFACE('',#694,3.75);
#696=CARTESIAN_POINT('',(-7.50000000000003,0.,-17.3749999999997));
#697=DIRECTION('',(0.,1.,0.));
#698=DIRECTION('',(0.,0.,1.));
#699=AXIS2_PLACEMENT_3D('',#696,#697,#698);
#700=CIRCLE('',#699,3.75);
#701=CARTESIAN_POINT('',(-4.41019822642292,0.,-19.4999999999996));
#702=VERTEX_POINT('',#701);
#703=EDGE_CURVE('E313',#670,#702,#700,.T.);
#704=ORIENTED_EDGE('',*,*,#703,.T.);
#705=DIRECTION('',(0.,-1.,0.));
#706=VECTOR('',#705,1.);
#707=CARTESIAN_POINT('',(-4.41019822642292,76.,-19.4999999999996));
#708=LINE('',#707,#706);
#709=CARTESIAN_POINT('',(-4.41019822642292,76.,-19.4999999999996));
#710=VERTEX_POINT('',#709);
#711=EDGE_CURVE('E421',#710,#702,#708,.T.);
#712=ORIENTED_EDGE('',*,*,#711,.F.);
#713=CARTESIAN_POINT('',(-7.50000000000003,76.,-17.3749999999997));
#714=DIRECTION('',(0.,1.,0.));
#715=DIRECTION('',(0.,0.,1.));
#716=AXIS2_PLACEMENT_3D('',#713,#714,#715);
#717=CIRCLE('',#716,3.75);
#718=EDGE_CURVE('E931',#678,#710,#717,.T.);
#719=ORIENTED_EDGE('',*,*,#718,.F.);
#720=ORIENTED_EDGE('',*,*,#679,.T.);
#721=EDGE_LOOP('',(#704,#712,#719,#720));
#722=FACE_BOUND('',#721,.T.);
#723=ADVANCED_FACE('F558',(#722),#695,.T.);
#724=CARTESIAN_POINT('',(25.9644660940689,0.,-19.4999999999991));
#725=VERTEX_POINT('',#724);
#726=EDGE_CURVE('E314',#725,#702,#668,.T.);
#727=ORIENTED_EDGE('',*,*,#726,.F.);
#728=DIRECTION('',(0.,-1.,0.));
#729=VECTOR('',#728,1.);
#730=CARTESIAN_POINT('',(25.9644660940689,76.,-19.4999999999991));
#731=LINE('',#730,#729);
#732=CARTESIAN_POINT('',(25.9644660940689,76.,-19.4999999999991));
#733=VERTEX_POINT('',#732);
#734=EDGE_CURVE('E419',#733,#725,#731,.T.);
#735=ORIENTED_EDGE('',*,*,#734,.F.);
#736=EDGE_CURVE('E930',#733,#710,#684,.T.);
#737=ORIENTED_EDGE('',*,*,#736,.T.);
#738=ORIENTED_EDGE('',*,*,#711,.T.);
#739=EDGE_LOOP('',(#727,#735,#737,#738));
#740=FACE_BOUND('',#739,.T.);
#741=ADVANCED_FACE('F497',(#740),#664,.T.);
#742=CARTESIAN_POINT('',(22.732233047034,76.,-22.732233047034));
#743=DIRECTION('',(-0.707106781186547,0.,0.707106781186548));
#744=DIRECTION('',(0.707106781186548,0.,0.707106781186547));
#745=AXIS2_PLACEMENT_3D('',#742,#743,#744);
#746=PLANE('',#745);
#747=DIRECTION('',(-0.707106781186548,0.,-0.707106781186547));
#748=VECTOR('',#747,1.);
#749=CARTESIAN_POINT('',(22.732233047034,0.,-22.732233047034));
#750=LINE('',#749,#748);
#751=CARTESIAN_POINT('',(27.0474132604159,0.,-18.4170528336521));
#752=VERTEX_POINT('',#751);
#753=EDGE_CURVE('E317',#752,#725,#750,.T.);
#754=ORIENTED_EDGE('',*,*,#753,.F.);
#755=DIRECTION('',(0.,-1.,0.));
#756=VECTOR('',#755,1.);
#757=CARTESIAN_POINT('',(27.0474132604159,76.,-18.4170528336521));
#758=LINE('',#757,#756);
#759=CARTESIAN_POINT('',(27.0474132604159,76.,-18.4170528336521));
#760=VERTEX_POINT('',#759);
#761=EDGE_CURVE('E417',#760,#752,#758,.T.);
#762=ORIENTED_EDGE('',*,*,#761,.F.);
#763=DIRECTION('',(-0.707106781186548,0.,-0.707106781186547));
#764=VECTOR('',#763,1.);
#765=CARTESIAN_POINT('',(22.732233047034,76.,-22.732233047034));
#766=LINE('',#765,#764);
#767=EDGE_CURVE('E493',#760,#733,#766,.T.);
#768=ORIENTED_EDGE('',*,*,#767,.T.);
#769=ORIENTED_EDGE('',*,*,#734,.T.);
#770=EDGE_LOOP('',(#754,#762,#768,#769));
#771=FACE_BOUND('',#770,.T.);
#772=ADVANCED_FACE('F489',(#771),#746,.T.);
#773=CARTESIAN_POINT('',(27.729631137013,76.,-14.7296311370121));
#774=DIRECTION('',(0.,-1.,0.));
#775=DIRECTION('',(0.,0.,-1.));
#776=AXIS2_PLACEMENT_3D('',#773,#774,#775);
#777=CYLINDRICAL_SURFACE('',#776,3.75);
#778=CARTESIAN_POINT('',(27.729631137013,0.,-14.7296311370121));
#779=DIRECTION('',(0.,1.,0.));
#780=DIRECTION('',(0.,0.,1.));
#781=AXIS2_PLACEMENT_3D('',#778,#779,#780);
#782=CIRCLE('',#781,3.75);
#783=CARTESIAN_POINT('',(31.417052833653,0.,-14.047413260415));
#784=VERTEX_POINT('',#783);
#785=EDGE_CURVE('E320',#752,#784,#782,.T.);
#786=ORIENTED_EDGE('',*,*,#785,.T.);
#787=DIRECTION('',(0.,-1.,0.));
#788=VECTOR('',#787,1.);
#789=CARTESIAN_POINT('',(31.417052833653,76.,-14.047413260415));
#790=LINE('',#789,#788);
#791=CARTESIAN_POINT('',(31.417052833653,76.,-14.047413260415));
#792=VERTEX_POINT('',#791);
#793=EDGE_CURVE('E415',#792,#784,#790,.T.);
#794=ORIENTED_EDGE('',*,*,#793,.F.);
#795=CARTESIAN_POINT('',(27.729631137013,76.,-14.7296311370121));
#796=DIRECTION('',(0.,1.,0.));
#797=DIRECTION('',(0.,0.,1.));
#798=AXIS2_PLACEMENT_3D('',#795,#796,#797);
#799=CIRCLE('',#798,3.75);
#800=EDGE_CURVE('E927',#760,#792,#799,.T.);
#801=ORIENTED_EDGE('',*,*,#800,.F.);
#802=ORIENTED_EDGE('',*,*,#761,.T.);
#803=EDGE_LOOP('',(#786,#794,#801,#802));
#804=FACE_BOUND('',#803,.T.);
#805=ADVANCED_FACE('F485',(#804),#777,.T.);
#806=CARTESIAN_POINT('',(32.5,0.,-12.964466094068));
#807=VERTEX_POINT('',#806);
#808=EDGE_CURVE('E321',#807,#784,#750,.T.);
#809=ORIENTED_EDGE('',*,*,#808,.F.);
#810=DIRECTION('',(0.,-1.,0.));
#811=VECTOR('',#810,1.);
#812=CARTESIAN_POINT('',(32.5,76.,-12.964466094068));
#813=LINE('',#812,#811);
#814=CARTESIAN_POINT('',(32.5,76.,-12.964466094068));
#815=VERTEX_POINT('',#814);
#816=EDGE_CURVE('E413',#815,#807,#813,.T.);
#817=ORIENTED_EDGE('',*,*,#816,.F.);
#818=EDGE_CURVE('E482',#815,#792,#766,.T.);
#819=ORIENTED_EDGE('',*,*,#818,.T.);
#820=ORIENTED_EDGE('',*,*,#793,.T.);
#821=EDGE_LOOP('',(#809,#817,#819,#820));
#822=FACE_BOUND('',#821,.T.);
#823=ADVANCED_FACE('F480',(#822),#746,.T.);
#824=CARTESIAN_POINT('',(32.5,76.,0.));
#825=DIRECTION('',(-1.,0.,0.));
#826=DIRECTION('',(0.,0.,1.));
#827=AXIS2_PLACEMENT_3D('',#824,#825,#826);
#828=PLANE('',#827);
#829=DIRECTION('',(0.,0.,-1.));
#830=VECTOR('',#829,1.);
#831=CARTESIAN_POINT('',(32.5,0.,0.));
#832=LINE('',#831,#830);
#833=CARTESIAN_POINT('',(32.5,0.,12.9644660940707));
#834=VERTEX_POINT('',#833);
#835=EDGE_CURVE('E324',#834,#807,#832,.T.);
#836=ORIENTED_EDGE('',*,*,#835,.F.);
#837=DIRECTION('',(0.,-1.,0.));
#838=VECTOR('',#837,1.);
#839=CARTESIAN_POINT('',(32.5,76.,12.9644660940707));
#840=LINE('',#839,#838);
#841=CARTESIAN_POINT('',(32.5,76.,12.9644660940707));
#842=VERTEX_POINT('',#841);
#843=EDGE_CURVE('E411',#842,#834,#840,.T.);
#844=ORIENTED_EDGE('',*,*,#843,.F.);
#845=DIRECTION('',(0.,0.,-1.));
#846=VECTOR('',#845,1.);
#847=CARTESIAN_POINT('',(32.5,76.,0.));
#848=LINE('',#847,#846);
#849=EDGE_CURVE('E476',#842,#815,#848,.T.);
#850=ORIENTED_EDGE('',*,*,#849,.T.);
#851=ORIENTED_EDGE('',*,*,#816,.T.);
#852=EDGE_LOOP('',(#836,#844,#850,#851));
#853=FACE_BOUND('',#852,.T.);
#854=ADVANCED_FACE('F473',(#853),#828,.T.);
#855=CARTESIAN_POINT('',(22.7322330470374,76.,22.7322330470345));
#856=DIRECTION('',(-0.707106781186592,0.,-0.707106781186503));
#857=DIRECTION('',(-0.707106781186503,0.,0.707106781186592));
#858=AXIS2_PLACEMENT_3D('',#855,#856,#857);
#859=PLANE('',#858);
#860=DIRECTION('',(0.707106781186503,0.,-0.707106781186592));
#861=VECTOR('',#860,1.);
#862=CARTESIAN_POINT('',(22.7322330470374,0.,22.7322330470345));
#863=LINE('',#862,#861);
#864=CARTESIAN_POINT('',(25.9644660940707,0.,19.5000000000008));
#865=VERTEX_POINT('',#864);
#866=EDGE_CURVE('E327',#865,#834,#863,.T.);
#867=ORIENTED_EDGE('',*,*,#866,.F.);
#868=DIRECTION('',(0.,-1.,0.));
#869=VECTOR('',#868,1.);
#870=CARTESIAN_POINT('',(25.9644660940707,76.,19.5000000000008));
#871=LINE('',#870,#869);
#872=CARTESIAN_POINT('',(25.9644660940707,76.,19.5000000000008));
#873=VERTEX_POINT('',#872);
#874=EDGE_CURVE('E409',#873,#865,#871,.T.);
#875=ORIENTED_EDGE('',*,*,#874,.F.);
#876=DIRECTION('',(0.707106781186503,0.,-0.707106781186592));
#877=VECTOR('',#876,1.);
#878=CARTESIAN_POINT('',(22.7322330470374,76.,22.7322330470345));
#879=LINE('',#878,#877);
#880=EDGE_CURVE('E924',#873,#842,#879,.T.);
#881=ORIENTED_EDGE('',*,*,#880,.T.);
#882=ORIENTED_EDGE('',*,*,#843,.T.);
#883=EDGE_LOOP('',(#867,#875,#881,#882));
#884=FACE_BOUND('',#883,.T.);
#885=ADVANCED_FACE('F467',(#884),#859,.T.);
#886=CARTESIAN_POINT('',(-3.06163442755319E-13,76.,19.5000000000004));
#887=DIRECTION('',(0.,0.,-1.));
#888=DIRECTION('',(-1.,0.,0.));
#889=AXIS2_PLACEMENT_3D('',#886,#887,#888);
#890=PLANE('',#889);
#891=DIRECTION('',(1.,0.,0.));
#892=VECTOR('',#891,1.);
#893=CARTESIAN_POINT('',(-3.06163442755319E-13,0.,19.5000000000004));
#894=LINE('',#893,#892);
#895=CARTESIAN_POINT('',(10.589801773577,0.,19.5000000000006));
#896=VERTEX_POINT('',#895);
#897=EDGE_CURVE('E330',#896,#865,#894,.T.);
#898=ORIENTED_EDGE('',*,*,#897,.F.);
#899=DIRECTION('',(0.,-1.,0.));
#900=VECTOR('',#899,1.);
#901=CARTESIAN_POINT('',(10.589801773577,76.,19.5000000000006));
#902=LINE('',#901,#900);
#903=CARTESIAN_POINT('',(10.589801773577,76.,19.5000000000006));
#904=VERTEX_POINT('',#903);
#905=EDGE_CURVE('E407',#904,#896,#902,.T.);
#906=ORIENTED_EDGE('',*,*,#905,.F.);
#907=DIRECTION('',(1.,0.,0.));
#908=VECTOR('',#907,1.);
#909=CARTESIAN_POINT('',(-3.06163442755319E-13,76.,19.5000000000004));
#910=LINE('',#909,#908);
#911=EDGE_CURVE('E463',#904,#873,#910,.T.);
#912=ORIENTED_EDGE('',*,*,#911,.T.);
#913=ORIENTED_EDGE('',*,*,#874,.T.);
#914=EDGE_LOOP('',(#898,#906,#912,#913));
#915=FACE_BOUND('',#914,.T.);
#916=ADVANCED_FACE('F458',(#915),#890,.T.);
#917=CARTESIAN_POINT('',(7.49999999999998,76.,17.3750000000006));
#918=DIRECTION('',(0.,-1.,0.));
#919=DIRECTION('',(0.,0.,-1.));
#920=AXIS2_PLACEMENT_3D('',#917,#918,#919);
#921=CYLINDRICAL_SURFACE('',#920,3.75);
#922=CARTESIAN_POINT('',(7.49999999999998,0.,17.3750000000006));
#923=DIRECTION('',(0.,1.,0.));
#924=DIRECTION('',(0.,0.,1.));
#925=AXIS2_PLACEMENT_3D('',#922,#923,#924);
#926=CIRCLE('',#925,3.75);
#927=CARTESIAN_POINT('',(4.41019822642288,0.,19.5000000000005));
#928=VERTEX_POINT('',#927);
#929=EDGE_CURVE('E333',#896,#928,#926,.T.);
#930=ORIENTED_EDGE('',*,*,#929,.T.);
#931=DIRECTION('',(0.,-1.,0.));
#932=VECTOR('',#931,1.);
#933=CARTESIAN_POINT('',(4.41019822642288,76.,19.5000000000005));
#934=LINE('',#933,#932);
#935=CARTESIAN_POINT('',(4.41019822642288,76.,19.5000000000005));
#936=VERTEX_POINT('',#935);
#937=EDGE_CURVE('E405',#936,#928,#934,.T.);
#938=ORIENTED_EDGE('',*,*,#937,.F.);
#939=CARTESIAN_POINT('',(7.49999999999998,76.,17.3750000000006));
#940=DIRECTION('',(0.,1.,0.));
#941=DIRECTION('',(0.,0.,1.));
#942=AXIS2_PLACEMENT_3D('',#939,#940,#941);
#943=CIRCLE('',#942,3.75);
#944=EDGE_CURVE('E919',#904,#936,#943,.T.);
#945=ORIENTED_EDGE('',*,*,#944,.F.);
#946=ORIENTED_EDGE('',*,*,#905,.T.);
#947=EDGE_LOOP('',(#930,#938,#945,#946));
#948=FACE_BOUND('',#947,.T.);
#949=ADVANCED_FACE('F545',(#948),#921,.T.);
#950=EDGE_CURVE('E334',#519,#928,#894,.T.);
#951=ORIENTED_EDGE('',*,*,#950,.F.);
#952=ORIENTED_EDGE('',*,*,#542,.F.);
#953=EDGE_CURVE('E452',#535,#936,#910,.T.);
#954=ORIENTED_EDGE('',*,*,#953,.T.);
#955=ORIENTED_EDGE('',*,*,#937,.T.);
#956=EDGE_LOOP('',(#951,#952,#954,#955));
#957=FACE_BOUND('',#956,.T.);
#958=ADVANCED_FACE('F451',(#957),#890,.T.);
#959=CARTESIAN_POINT('',(7.49999999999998,76.,17.3750000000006));
#960=DIRECTION('',(0.,-1.,0.));
#961=DIRECTION('',(0.,0.,-1.));
#962=AXIS2_PLACEMENT_3D('',#959,#960,#961);
#963=CYLINDRICAL_SURFACE('',#962,2.125);
#964=CARTESIAN_POINT('',(7.49999999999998,76.,17.3750000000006));
#965=DIRECTION('',(0.,1.,0.));
#966=DIRECTION('',(0.,0.,1.));
#967=AXIS2_PLACEMENT_3D('',#964,#965,#966);
#968=CIRCLE('',#967,2.125);
#969=CARTESIAN_POINT('',(7.49999999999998,76.,19.5000000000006));
#970=VERTEX_POINT('',#969);
#971=EDGE_CURVE('E940',#970,#970,#968,.T.);
#972=ORIENTED_EDGE('',*,*,#971,.T.);
#973=EDGE_LOOP('',(#972));
#974=FACE_BOUND('',#973,.T.);
#975=CARTESIAN_POINT('',(7.49999999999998,0.,17.3750000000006));
#976=DIRECTION('',(0.,1.,0.));
#977=DIRECTION('',(0.,0.,1.));
#978=AXIS2_PLACEMENT_3D('',#975,#976,#977);
#979=CIRCLE('',#978,2.125);
#980=CARTESIAN_POINT('',(7.49999999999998,0.,19.5000000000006));
#981=VERTEX_POINT('',#980);
#982=EDGE_CURVE('E294',#981,#981,#979,.T.);
#983=ORIENTED_EDGE('',*,*,#982,.F.);
#984=EDGE_LOOP('',(#983));
#985=FACE_BOUND('',#984,.T.);
#986=ADVANCED_FACE('F544',(#974,#985),#963,.F.);
#987=CARTESIAN_POINT('',(27.729631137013,76.,-14.7296311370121));
#988=DIRECTION('',(0.,-1.,0.));
#989=DIRECTION('',(0.,0.,-1.));
#990=AXIS2_PLACEMENT_3D('',#987,#988,#989);
#991=CYLINDRICAL_SURFACE('',#990,2.125);
#992=CARTESIAN_POINT('',(27.729631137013,76.,-14.7296311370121));
#993=DIRECTION('',(0.,1.,0.));
#994=DIRECTION('',(0.,0.,1.));
#995=AXIS2_PLACEMENT_3D('',#992,#993,#994);
#996=CIRCLE('',#995,2.125);
#997=CARTESIAN_POINT('',(27.729631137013,76.,-12.6046311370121));
#998=VERTEX_POINT('',#997);
#999=EDGE_CURVE('E943',#998,#998,#996,.T.);
#1000=ORIENTED_EDGE('',*,*,#999,.T.);
#1001=EDGE_LOOP('',(#1000));
#1002=FACE_BOUND('',#1001,.T.);
#1003=CARTESIAN_POINT('',(27.729631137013,0.,-14.7296311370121));
#1004=DIRECTION('',(0.,1.,0.));
#1005=DIRECTION('',(0.,0.,1.));
#1006=AXIS2_PLACEMENT_3D('',#1003,#1004,#1005);
#1007=CIRCLE('',#1006,2.125);
#1008=CARTESIAN_POINT('',(27.729631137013,0.,-12.6046311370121));
#1009=VERTEX_POINT('',#1008);
#1010=EDGE_CURVE('E291',#1009,#1009,#1007,.T.);
#1011=ORIENTED_EDGE('',*,*,#1010,.F.);
#1012=EDGE_LOOP('',(#1011));
#1013=FACE_BOUND('',#1012,.T.);
#1014=ADVANCED_FACE('F626',(#1002,#1013),#991,.F.);
#1015=CARTESIAN_POINT('',(-7.50000000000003,76.,-17.3749999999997));
#1016=DIRECTION('',(0.,-1.,0.));
#1017=DIRECTION('',(0.,0.,-1.));
#1018=AXIS2_PLACEMENT_3D('',#1015,#1016,#1017);
#1019=CYLINDRICAL_SURFACE('',#1018,2.125);
#1020=CARTESIAN_POINT('',(-7.50000000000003,76.,-17.3749999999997));
#1021=DIRECTION('',(0.,1.,0.));
#1022=DIRECTION('',(0.,0.,1.));
#1023=AXIS2_PLACEMENT_3D('',#1020,#1021,#1022);
#1024=CIRCLE('',#1023,2.125);
#1025=CARTESIAN_POINT('',(-7.50000000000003,76.,-15.2499999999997));
#1026=VERTEX_POINT('',#1025);
#1027=EDGE_CURVE('E946',#1026,#1026,#1024,.T.);
#1028=ORIENTED_EDGE('',*,*,#1027,.T.);
#1029=EDGE_LOOP('',(#1028));
#1030=FACE_BOUND('',#1029,.T.);
#1031=CARTESIAN_POINT('',(-7.50000000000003,0.,-17.3749999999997));
#1032=DIRECTION('',(0.,1.,0.));
#1033=DIRECTION('',(0.,0.,1.));
#1034=AXIS2_PLACEMENT_3D('',#1031,#1032,#1033);
#1035=CIRCLE('',#1034,2.125);
#1036=CARTESIAN_POINT('',(-7.50000000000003,0.,-15.2499999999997));
#1037=VERTEX_POINT('',#1036);
#1038=EDGE_CURVE('E288',#1037,#1037,#1035,.T.);
#1039=ORIENTED_EDGE('',*,*,#1038,.F.);
#1040=EDGE_LOOP('',(#1039));
#1041=FACE_BOUND('',#1040,.T.);
#1042=ADVANCED_FACE('F635',(#1030,#1041),#1019,.F.);
#1043=CARTESIAN_POINT('',(-27.7296311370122,76.,14.7296311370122));
#1044=DIRECTION('',(0.,-1.,0.));
#1045=DIRECTION('',(0.,0.,-1.));
#1046=AXIS2_PLACEMENT_3D('',#1043,#1044,#1045);
#1047=CYLINDRICAL_SURFACE('',#1046,2.125);
#1048=CARTESIAN_POINT('',(-27.7296311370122,76.,14.7296311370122));
#1049=DIRECTION('',(0.,1.,0.));
#1050=DIRECTION('',(0.,0.,1.));
#1051=AXIS2_PLACEMENT_3D('',#1048,#1049,#1050);
#1052=CIRCLE('',#1051,2.125);
#1053=CARTESIAN_POINT('',(-27.7296311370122,76.,16.8546311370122));
#1054=VERTEX_POINT('',#1053);
#1055=EDGE_CURVE('E367',#1054,#1054,#1052,.T.);
#1056=ORIENTED_EDGE('',*,*,#1055,.T.);
#1057=EDGE_LOOP('',(#1056));
#1058=FACE_BOUND('',#1057,.T.);
#1059=CARTESIAN_POINT('',(-27.7296311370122,0.,14.7296311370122));
#1060=DIRECTION('',(0.,1.,0.));
#1061=DIRECTION('',(0.,0.,1.));
#1062=AXIS2_PLACEMENT_3D('',#1059,#1060,#1061);
#1063=CIRCLE('',#1062,2.125);
#1064=CARTESIAN_POINT('',(-27.7296311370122,0.,16.8546311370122));
#1065=VERTEX_POINT('',#1064);
#1066=EDGE_CURVE('E285',#1065,#1065,#1063,.T.);
#1067=ORIENTED_EDGE('',*,*,#1066,.F.);
#1068=EDGE_LOOP('',(#1067));
#1069=FACE_BOUND('',#1068,.T.);
#1070=ADVANCED_FACE('F43',(#1058,#1069),#1047,.F.);
#1071=CARTESIAN_POINT('',(33.,76.,-13.1715728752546));
#1072=DIRECTION('',(0.,-1.,0.));
#1073=DIRECTION('',(0.,0.,-1.));
#1074=AXIS2_PLACEMENT_3D('',#1071,#1072,#1073);
#1075=CYLINDRICAL_SURFACE('',#1074,1.99999999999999);
#1076=CARTESIAN_POINT('',(33.,0.,-13.1715728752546));
#1077=DIRECTION('',(0.,1.,0.));
#1078=DIRECTION('',(0.,0.,1.));
#1079=AXIS2_PLACEMENT_3D('',#1076,#1077,#1078);
#1080=CIRCLE('',#1079,1.99999999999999);
#1081=EDGE_CURVE('E167',#486,#29,#1080,.T.);
#1082=ORIENTED_EDGE('',*,*,#1081,.T.);
#1083=ORIENTED_EDGE('',*,*,#54,.F.);
#1084=CARTESIAN_POINT('',(33.,76.,-13.1715728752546));
#1085=DIRECTION('',(0.,1.,0.));
#1086=DIRECTION('',(0.,0.,1.));
#1087=AXIS2_PLACEMENT_3D('',#1084,#1085,#1086);
#1088=CIRCLE('',#1087,1.99999999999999);
#1089=EDGE_CURVE('E60',#494,#47,#1088,.T.);
#1090=ORIENTED_EDGE('',*,*,#1089,.F.);
#1091=ORIENTED_EDGE('',*,*,#495,.T.);
#1092=EDGE_LOOP('',(#1082,#1083,#1090,#1091));
#1093=FACE_BOUND('',#1092,.T.);
#1094=ADVANCED_FACE('F651',(#1093),#1075,.T.);
#1095=CARTESIAN_POINT('',(0.,76.,0.));
#1096=DIRECTION('',(0.,1.,0.));
#1097=DIRECTION('',(0.,0.,1.));
#1098=AXIS2_PLACEMENT_3D('',#1095,#1096,#1097);
#1099=PLANE('',#1098);
#1100=ORIENTED_EDGE('',*,*,#1055,.F.);
#1101=EDGE_LOOP('',(#1100));
#1102=FACE_BOUND('',#1101,.T.);
#1103=ORIENTED_EDGE('',*,*,#1027,.F.);
#1104=EDGE_LOOP('',(#1103));
#1105=FACE_BOUND('',#1104,.T.);
#1106=ORIENTED_EDGE('',*,*,#999,.F.);
#1107=EDGE_LOOP('',(#1106));
#1108=FACE_BOUND('',#1107,.T.);
#1109=ORIENTED_EDGE('',*,*,#971,.F.);
#1110=EDGE_LOOP('',(#1109));
#1111=FACE_BOUND('',#1110,.T.);
#1112=ORIENTED_EDGE('',*,*,#536,.F.);
#1113=ORIENTED_EDGE('',*,*,#574,.T.);
#1114=ORIENTED_EDGE('',*,*,#592,.F.);
#1115=ORIENTED_EDGE('',*,*,#623,.F.);
#1116=ORIENTED_EDGE('',*,*,#654,.F.);
#1117=ORIENTED_EDGE('',*,*,#685,.F.);
#1118=ORIENTED_EDGE('',*,*,#718,.T.);
#1119=ORIENTED_EDGE('',*,*,#736,.F.);
#1120=ORIENTED_EDGE('',*,*,#767,.F.);
#1121=ORIENTED_EDGE('',*,*,#800,.T.);
#1122=ORIENTED_EDGE('',*,*,#818,.F.);
#1123=ORIENTED_EDGE('',*,*,#849,.F.);
#1124=ORIENTED_EDGE('',*,*,#880,.F.);
#1125=ORIENTED_EDGE('',*,*,#911,.F.);
#1126=ORIENTED_EDGE('',*,*,#944,.T.);
#1127=ORIENTED_EDGE('',*,*,#953,.F.);
#1128=EDGE_LOOP('',(#1112,#1113,#1114,#1115,#1116,#1117,#1118,#1119,#1120,#1121,#1122,#1123,
#1124,#1125,#1126,#1127));
#1129=FACE_BOUND('',#1128,.T.);
#1130=ORIENTED_EDGE('',*,*,#48,.T.);
#1131=ORIENTED_EDGE('',*,*,#86,.T.);
#1132=ORIENTED_EDGE('',*,*,#117,.T.);
#1133=ORIENTED_EDGE('',*,*,#150,.T.);
#1134=ORIENTED_EDGE('',*,*,#181,.T.);
#1135=ORIENTED_EDGE('',*,*,#214,.T.);
#1136=ORIENTED_EDGE('',*,*,#245,.T.);
#1137=ORIENTED_EDGE('',*,*,#278,.T.);
#1138=ORIENTED_EDGE('',*,*,#309,.T.);
#1139=ORIENTED_EDGE('',*,*,#342,.T.);
#1140=ORIENTED_EDGE('',*,*,#373,.T.);
#1141=ORIENTED_EDGE('',*,*,#406,.T.);
#1142=ORIENTED_EDGE('',*,*,#437,.T.);
#1143=ORIENTED_EDGE('',*,*,#470,.T.);
#1144=ORIENTED_EDGE('',*,*,#501,.T.);
#1145=ORIENTED_EDGE('',*,*,#1089,.T.);
#1146=EDGE_LOOP('',(#1130,#1131,#1132,#1133,#1134,#1135,#1136,#1137,#1138,#1139,#1140,#1141,
#1142,#1143,#1144,#1145));
#1147=FACE_BOUND('',#1146,.T.);
#1148=ADVANCED_FACE('F263',(#1102,#1105,#1108,#1111,#1129,#1147),#1099,.T.);
#1149=CARTESIAN_POINT('',(0.,0.,0.));
#1150=DIRECTION('',(0.,1.,0.));
#1151=DIRECTION('',(0.,0.,1.));
#1152=AXIS2_PLACEMENT_3D('',#1149,#1150,#1151);
#1153=PLANE('',#1152);
#1154=ORIENTED_EDGE('',*,*,#1066,.T.);
#1155=EDGE_LOOP('',(#1154));
#1156=FACE_BOUND('',#1155,.T.);
#1157=ORIENTED_EDGE('',*,*,#1038,.T.);
#1158=EDGE_LOOP('',(#1157));
#1159=FACE_BOUND('',#1158,.T.);
#1160=ORIENTED_EDGE('',*,*,#1010,.T.);
#1161=EDGE_LOOP('',(#1160));
#1162=FACE_BOUND('',#1161,.T.);
#1163=ORIENTED_EDGE('',*,*,#982,.T.);
#1164=EDGE_LOOP('',(#1163));
#1165=FACE_BOUND('',#1164,.T.);
#1166=ORIENTED_EDGE('',*,*,#520,.T.);
#1167=ORIENTED_EDGE('',*,*,#950,.T.);
#1168=ORIENTED_EDGE('',*,*,#929,.F.);
#1169=ORIENTED_EDGE('',*,*,#897,.T.);
#1170=ORIENTED_EDGE('',*,*,#866,.T.);
#1171=ORIENTED_EDGE('',*,*,#835,.T.);
#1172=ORIENTED_EDGE('',*,*,#808,.T.);
#1173=ORIENTED_EDGE('',*,*,#785,.F.);
#1174=ORIENTED_EDGE('',*,*,#753,.T.);
#1175=ORIENTED_EDGE('',*,*,#726,.T.);
#1176=ORIENTED_EDGE('',*,*,#703,.F.);
#1177=ORIENTED_EDGE('',*,*,#671,.T.);
#1178=ORIENTED_EDGE('',*,*,#640,.T.);
#1179=ORIENTED_EDGE('',*,*,#609,.T.);
#1180=ORIENTED_EDGE('',*,*,#582,.T.);
#1181=ORIENTED_EDGE('',*,*,#559,.F.);
#1182=EDGE_LOOP('',(#1166,#1167,#1168,#1169,#1170,#1171,#1172,#1173,#1174,#1175,#1176,#1177,
#1178,#1179,#1180,#1181));
#1183=FACE_BOUND('',#1182,.T.);
#1184=ORIENTED_EDGE('',*,*,#32,.F.);
#1185=ORIENTED_EDGE('',*,*,#1081,.F.);
#1186=ORIENTED_EDGE('',*,*,#487,.F.);
#1187=ORIENTED_EDGE('',*,*,#455,.F.);
#1188=ORIENTED_EDGE('',*,*,#423,.F.);
#1189=ORIENTED_EDGE('',*,*,#391,.F.);
#1190=ORIENTED_EDGE('',*,*,#359,.F.);
#1191=ORIENTED_EDGE('',*,*,#327,.F.);
#1192=ORIENTED_EDGE('',*,*,#295,.F.);
#1193=ORIENTED_EDGE('',*,*,#263,.F.);
#1194=ORIENTED_EDGE('',*,*,#231,.F.);
#1195=ORIENTED_EDGE('',*,*,#199,.F.);
#1196=ORIENTED_EDGE('',*,*,#167,.F.);
#1197=ORIENTED_EDGE('',*,*,#135,.F.);
#1198=ORIENTED_EDGE('',*,*,#103,.F.);
#1199=ORIENTED_EDGE('',*,*,#71,.F.);
#1200=EDGE_LOOP('',(#1184,#1185,#1186,#1187,#1188,#1189,#1190,#1191,#1192,#1193,#1194,#1195,
#1196,#1197,#1198,#1199));
#1201=FACE_BOUND('',#1200,.T.);
#1202=ADVANCED_FACE('F442',(#1156,#1159,#1162,#1165,#1183,#1201),#1153,.F.);
#1203=CLOSED_SHELL('',(#58,#91,#122,#155,#186,#219,#250,#283,#314,#347,#378,#411,#442,#475,#506,
#546,#579,#597,#628,#659,#690,#723,#741,#772,#805,#823,#854,#885,#916,#949,#958,#986,#1014,
#1042,#1070,#1094,#1148,#1202));
#1204=MANIFOLD_SOLID_BREP('B2',#1203);
#1205=ADVANCED_BREP_SHAPE_REPRESENTATION('',(#18,#1204),#14);
#1206=SHAPE_DEFINITION_REPRESENTATION(#9,#1205);
ENDSEC;
END-ISO-10303-21;
